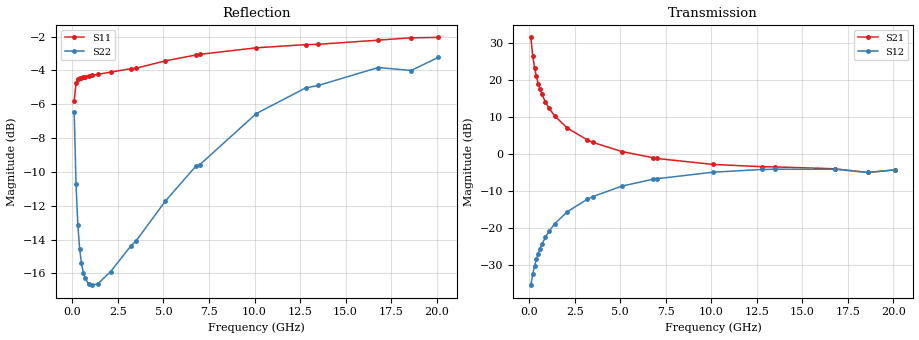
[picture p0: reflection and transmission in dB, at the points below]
!  Infineon Technologies AG
! BFR380L3 , PF131585-7, No.6, Th 09.10.01, soldered on pcb-board, measured with PP GSG850
!  Vce=1.75 V,  Ic=75.0 mA
! Common Emitter S-Parameters:  15. November 2001
#  GHz  S  MA  R  50
! f  S11  S21  S12  S22
! GHz  Mag  Ang  Mag  Ang  Mag  Ang  Mag  Ang
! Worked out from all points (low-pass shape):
!   201 points, 100 MHz to 20.1 GHz, reference 50 ohm
!   highest |S21| = 31.45 dB at 100 MHz (marker M1); lowest = -5.0 dB at 18.6 GHz (marker M2)
!   |S21| within 3 dB of the highest: start of sweep to 161.3 MHz
!   lowest |S11| = -5.8 dB at 100 MHz (marker M3), VSWR 3.10, Z = 19.4 - j21 ohm
!   |S11| at or under -10 dB: nowhere
!   |S22| runs from -16.7 to -3.2 dB; largest |S21 - S12| = 37
!   S11 on the Smith chart (normalised r, x): 100 MHz: 0.39, -0.42; 600 MHz: 0.25, -0.01; 3.2 GHz: 0.25, +0.37; 7 GHz: 0.31, +0.85; 12.8 GHz: 0.53, +1.59; 20.1 GHz: 1.03, +2.61
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0.1  0.5126 -128.8  37.35 122.6  0.0171 56.6  0.4745 -67.8
0.2  0.5785 -154.4  21.26 105.5  0.02382 57.6  0.291 -94.2
0.3  0.5943 -164.9  14.62 98.2  0.03075 62.3  0.2203 -109.3
0.4  0.5974 -171.1  11.1 93.6  0.03789 65.3  0.1872 -120.1
0.5  0.6005 -175.3  8.927 90.0  0.04534 67.5  0.1696 -128.3
0.6  0.6026 -178.7  7.469 87.3  0.0529 69.0  0.1594 -134.6
0.7  0.6041 178.5  6.427 84.8  0.06038 70.0  0.1535 -139.7
0.9  0.6078 173.8  5.024 80.5  0.07571 70.7  0.1471 -147.2
1.1  0.6101 169.8  4.14 76.7  0.09117 70.6  0.1464 -152.4
1.4  0.614 164.4  3.281 71.4  0.114 69.8  0.1478 -158.1
2.1  0.6234 153.3  2.242 60.3  0.1668 66.1  0.1605 -166.9
3.2  0.6379 137.6  1.549 45.1  0.2459 58.5  0.1909 -178.0
3.5  0.6404 133.8  1.436 41.3  0.2673 56.2  0.1979 179.9
5.1  0.673 115.1  1.08 24.0  0.3694 43.9  0.259 164.2
6.8  0.7008 98.1  0.8923 10.0  0.457 31.4  0.3299 146.7
7  0.7036 96.3  0.8718 8.7  0.464 29.8  0.3323 146.0
10.1  0.7357 73.9  0.7246 -8.2  0.5691 9.1  0.4704 118.9
12.8  0.7517 60.4  0.6748 -19.8  0.6192 -7.5  0.5597 97.8
13.5  0.7534 57.4  0.6702 -22.4  0.6238 -11.4  0.5693 93.5
16.8  0.775 46.1  0.6324 -33.2  0.6228 -26.8  0.6434 73.9
18.6  0.7875 43.3  0.5639 -38.5  0.5642 -33.6  0.6304 69.2
20.1  0.7897 37.2  0.6111 -44.0  0.6134 -39.9  0.6896 58.6
